VERSION 5.8 ;
BUSBITCHARS "[]" ;
DIVIDERCHAR "/" ;

UNITS
  DATABASE MICRONS 1000 ;
END UNITS

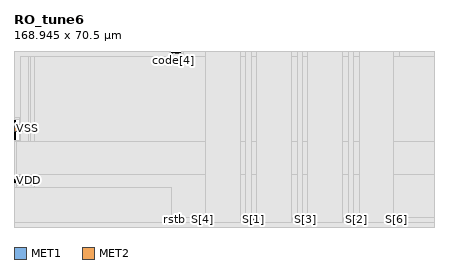
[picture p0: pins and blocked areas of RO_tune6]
MACRO RO_tune6
  CLASS BLOCK ;
  ORIGIN 68.7 88.515 ;
  FOREIGN RO_tune6 -68.7 -88.515 ;
  SIZE 168.945 BY 70.5 ;
  SYMMETRY X Y R90 ;
  PIN code[0]
    DIRECTION INPUT ;
    USE SIGNAL ;
    PORT
      LAYER MET1 ;
        RECT -2.775 -18.885 -2.545 -18.655 ;
    END
  END code[0]
  PIN code[7]
    DIRECTION INPUT ;
    USE SIGNAL ;
    PORT
      LAYER MET1 ;
        RECT -1.805 -18.885 -1.575 -18.655 ;
    END
  END code[7]
  PIN S[0]
    DIRECTION OUTPUT ;
    USE SIGNAL ;
    PORT
      LAYER MET2 ;
        RECT 23.305 -85.825 23.585 -85.545 ;
    END
  END S[0]
  PIN S[7]
    DIRECTION OUTPUT ;
    USE SIGNAL ;
    PORT
      LAYER MET2 ;
        RECT 64.455 -85.825 64.735 -85.545 ;
    END
  END S[7]
  PIN rstb
    DIRECTION INPUT ;
    USE SIGNAL ;
    PORT
      LAYER MET2 ;
        RECT -4.295 -85.825 -4.015 -85.545 ;
    END
  END rstb
  PIN code[1]
    DIRECTION INPUT ;
    USE SIGNAL ;
    PORT
      LAYER MET1 ;
        RECT -3.26 -18.885 -3.03 -18.655 ;
    END
  END code[1]
  PIN code[2]
    DIRECTION INPUT ;
    USE SIGNAL ;
    PORT
      LAYER MET1 ;
        RECT -3.745 -18.885 -3.515 -18.655 ;
    END
  END code[2]
  PIN code[3]
    DIRECTION INPUT ;
    USE SIGNAL ;
    PORT
      LAYER MET1 ;
        RECT -4.23 -18.885 -4 -18.655 ;
    END
  END code[3]
  PIN code[4]
    DIRECTION INPUT ;
    USE SIGNAL ;
    PORT
      LAYER MET1 ;
        RECT -4.715 -18.885 -4.485 -18.655 ;
    END
  END code[4]
  PIN code[5]
    DIRECTION INPUT ;
    USE SIGNAL ;
    PORT
      LAYER MET1 ;
        RECT -5.2 -18.885 -4.97 -18.655 ;
    END
  END code[5]
  PIN code[6]
    DIRECTION INPUT ;
    USE SIGNAL ;
    PORT
      LAYER MET1 ;
        RECT -2.29 -18.885 -2.06 -18.655 ;
    END
  END code[6]
  PIN VDD
    DIRECTION INOUT ;
    USE POWER ;
    PORT
      LAYER MET1 ;
        RECT -66.67 -71.56 -61.525 -68.325 ;
    END
  END VDD
  PIN VSS
    DIRECTION INOUT ;
    USE GROUND ;
    PORT
      LAYER MET2 ;
        RECT -68.64 -50.215 -63.035 -47.215 ;
    END
  END VSS
  PIN S[2]
    DIRECTION OUTPUT ;
    USE SIGNAL ;
    PORT
      LAYER MET2 ;
        RECT 68.805 -85.825 69.085 -85.545 ;
    END
  END S[2]
  PIN S[6]
    DIRECTION OUTPUT ;
    USE SIGNAL ;
    PORT
      LAYER MET2 ;
        RECT 85.03 -85.825 85.31 -85.545 ;
    END
  END S[6]
  PIN S[3]
    DIRECTION OUTPUT ;
    USE SIGNAL ;
    PORT
      LAYER MET2 ;
        RECT 48.23 -85.825 48.51 -85.545 ;
    END
  END S[3]
  PIN S[1]
    DIRECTION OUTPUT ;
    USE SIGNAL ;
    PORT
      LAYER MET2 ;
        RECT 27.655 -85.825 27.935 -85.545 ;
    END
  END S[1]
  PIN S[5]
    DIRECTION OUTPUT ;
    USE SIGNAL ;
    PORT
      LAYER MET2 ;
        RECT 43.91 -85.825 44.19 -85.545 ;
    END
  END S[5]
  PIN S[4]
    DIRECTION OUTPUT ;
    USE SIGNAL ;
    PORT
      LAYER MET2 ;
        RECT 7.08 -85.825 7.36 -85.545 ;
    END
  END S[4]
  OBS
    # MPTDC_OPTION_B2_PG_ACCESS_CUT
    LAYER MET1 ;
      RECT 99.25 -67.175 99.55 -57.125 ;
      RECT 98.13 -67.175 98.43 -57.125 ;
      RECT 97.01 -67.175 97.31 -57.125 ;
      RECT 95.89 -67.175 96.19 -57.125 ;
      RECT 95.76 -67.175 100.24 -66.755 ;
      RECT 99.81 -66.425 100.11 -46.325 ;
      RECT 98.69 -66.425 98.99 -46.325 ;
      RECT 97.57 -66.425 97.87 -46.325 ;
      RECT 96.45 -66.425 96.75 -46.325 ;
      RECT 95.76 -56.795 100.24 -55.955 ;
      RECT 99.25 -55.625 99.55 -35.525 ;
      RECT 98.13 -55.625 98.43 -35.525 ;
      RECT 97.01 -55.625 97.31 -35.525 ;
      RECT 95.89 -55.625 96.19 -35.525 ;
      RECT 95.76 -45.995 100.24 -45.155 ;
      RECT 99.81 -44.825 100.11 -24.725 ;
      RECT 98.69 -44.825 98.99 -24.725 ;
      RECT 97.57 -44.825 97.87 -24.725 ;
      RECT 96.45 -44.825 96.75 -24.725 ;
      RECT 95.76 -35.195 100.24 -34.355 ;
      RECT 95.76 -24.395 100.24 -23.975 ;
      RECT 99.25 -34.025 99.55 -23.975 ;
      RECT 98.13 -34.025 98.43 -23.975 ;
      RECT 97.01 -34.025 97.31 -23.975 ;
      RECT 95.89 -34.025 96.19 -23.975 ;
      RECT -1.805 -23.44 -1.575 -19.485 ;
      RECT -24.275 -23.465 -23.895 -23.185 ;
      RECT -24.275 -23.44 -1.575 -23.21 ;
      RECT -2.29 -22.955 -2.06 -19.485 ;
      RECT -29.065 -22.98 -28.685 -22.7 ;
      RECT -29.065 -22.955 -2.06 -22.725 ;
      RECT -2.775 -22.47 -2.545 -19.485 ;
      RECT -33.855 -22.495 -33.475 -22.215 ;
      RECT -33.855 -22.47 -2.545 -22.24 ;
      RECT -3.26 -21.985 -3.03 -19.485 ;
      RECT -38.645 -22.01 -38.265 -21.73 ;
      RECT -38.645 -21.985 -3.03 -21.755 ;
      RECT -3.745 -21.5 -3.515 -19.485 ;
      RECT -43.435 -21.525 -43.055 -21.245 ;
      RECT -43.435 -21.5 -3.515 -21.27 ;
      RECT -4.23 -21.015 -4 -19.485 ;
      RECT -48.285 -21.04 -47.905 -20.76 ;
      RECT -48.285 -21.015 -4 -20.785 ;
      RECT -4.715 -20.53 -4.485 -19.485 ;
      RECT -53.1 -20.555 -52.72 -20.275 ;
      RECT -53.1 -20.53 -4.485 -20.3 ;
      RECT -5.2 -20.045 -4.97 -19.485 ;
      RECT -57.805 -20.07 -57.425 -19.79 ;
      RECT -57.805 -20.045 -4.97 -19.815 ;
      RECT -68.695 -83.02 -67.015 -70.943 ;
      RECT -68.695 -68.942 -67.015 -53.915 ;
      RECT -68.695 -83.02 -8.41 -78.02 ;
      RECT -66.67 -67.725 -64.99 -36.465 ;
      RECT -68.695 -45.05 -67.015 -36.465 ;
      RECT -1.155 -88.515 100.245 -18.015 ;
      RECT -68.7 -45.23 -5.62 -18.015 ;
      RECT -60.525 -88.515 100.245 -19.305 ;
      RECT -61.105 -88.515 -60.525 -70.943 ;
      RECT -61.105 -68.942 -60.525 -19.305 ;
      RECT -66.67 -67.905 100.245 -19.305 ;
      RECT -68.7 -67.905 100.245 -53.735 ;
      RECT -68.7 -88.515 -67.015 -70.943 ;
      RECT -68.7 -68.942 -67.015 -53.735 ;
      RECT -68.7 -88.515 100.245 -71.98 ;
    LAYER MET2 ;
      RECT 99.26 -67.175 99.54 -57.125 ;
      RECT 98.14 -67.175 98.42 -57.125 ;
      RECT 97.02 -67.175 97.3 -57.125 ;
      RECT 95.9 -67.175 96.18 -57.125 ;
      RECT 95.76 -67.175 100.24 -66.775 ;
      RECT 99.82 -66.425 100.1 -46.325 ;
      RECT 98.7 -66.425 98.98 -46.325 ;
      RECT 97.58 -66.425 97.86 -46.325 ;
      RECT 96.46 -66.425 96.74 -46.325 ;
      RECT 95.76 -56.775 100.24 -55.975 ;
      RECT 99.26 -55.625 99.54 -35.525 ;
      RECT 98.14 -55.625 98.42 -35.525 ;
      RECT 97.02 -55.625 97.3 -35.525 ;
      RECT 95.9 -55.625 96.18 -35.525 ;
      RECT 95.76 -45.975 100.24 -45.175 ;
      RECT 99.82 -44.825 100.1 -24.725 ;
      RECT 98.7 -44.825 98.98 -24.725 ;
      RECT 97.58 -44.825 97.86 -24.725 ;
      RECT 96.46 -44.825 96.74 -24.725 ;
      RECT 95.76 -35.175 100.24 -34.375 ;
      RECT 95.76 -24.375 100.24 -23.975 ;
      RECT 99.26 -34.025 99.54 -23.975 ;
      RECT 98.14 -34.025 98.42 -23.975 ;
      RECT 97.02 -34.025 97.3 -23.975 ;
      RECT 95.9 -34.025 96.18 -23.975 ;
      RECT -11.66 -22.655 34.925 -18.655 ;
      RECT -68.64 -58.215 -63.415 -55.215 ;
      RECT -68.64 -66.215 -63.575 -63.215 ;
      RECT -0.575 -85.125 100.245 -18.015 ;
      RECT 85.73 -88.515 100.245 -18.015 ;
      RECT -68.7 -44.65 -6.2 -18.015 ;
      RECT -3.595 -88.515 6.66 -18.655 ;
      RECT -62.035 -67.325 100.245 -18.655 ;
      RECT -62.985 -67.325 -62.035 -49.715 ;
      RECT -62.985 -47.715 -62.035 -18.655 ;
      RECT -66.015 -67.325 -62.985 -50.265 ;
      RECT -66.015 -47.165 -62.985 -18.655 ;
      RECT -60.525 -85.125 100.245 -18.655 ;
      RECT -62.035 -50.215 100.245 -47.215 ;
      RECT -62.985 -50.215 -62.035 -49.715 ;
      RECT -62.985 -47.715 -62.035 -47.215 ;
      RECT -68.7 -67.325 100.245 -54.315 ;
      RECT -68.7 -88.515 -67.67 -70.943 ;
      RECT -68.7 -68.942 -67.67 -54.315 ;
      RECT -68.7 -88.515 -4.715 -72.56 ;
      RECT 69.505 -88.515 84.61 -18.015 ;
      RECT 65.155 -88.515 68.385 -18.015 ;
      RECT 48.93 -88.515 64.035 -18.015 ;
      RECT 44.61 -88.515 47.81 -18.015 ;
      RECT 28.355 -88.515 43.49 -18.015 ;
      RECT 24.005 -88.515 27.235 -18.015 ;
      RECT 7.78 -88.515 22.885 -18.015 ;
      RECT -68.7 -88.515 100.245 -86.245 ;
    LAYER MET3 ;
      RECT 99.26 -67.175 99.54 -57.325 ;
      RECT 98.14 -67.175 98.42 -57.325 ;
      RECT 97.02 -67.175 97.3 -57.325 ;
      RECT 95.9 -67.175 96.18 -57.325 ;
      RECT 95.76 -67.175 100.24 -66.575 ;
      RECT 99.82 -66.225 100.1 -46.525 ;
      RECT 98.7 -66.225 98.98 -46.525 ;
      RECT 97.58 -66.225 97.86 -46.525 ;
      RECT 96.46 -66.225 96.74 -46.525 ;
      RECT 95.76 -56.975 100.24 -55.775 ;
      RECT 99.26 -55.425 99.54 -35.725 ;
      RECT 98.14 -55.425 98.42 -35.725 ;
      RECT 97.02 -55.425 97.3 -35.725 ;
      RECT 95.9 -55.425 96.18 -35.725 ;
      RECT 95.76 -46.175 100.24 -44.975 ;
      RECT 99.82 -44.625 100.1 -24.925 ;
      RECT 98.7 -44.625 98.98 -24.925 ;
      RECT 97.58 -44.625 97.86 -24.925 ;
      RECT 96.46 -44.625 96.74 -24.925 ;
      RECT 95.76 -35.375 100.24 -34.175 ;
      RECT 95.76 -24.575 100.24 -23.975 ;
      RECT 99.26 -33.825 99.54 -23.975 ;
      RECT 98.14 -33.825 98.42 -23.975 ;
      RECT 97.02 -33.825 97.3 -23.975 ;
      RECT 95.9 -33.825 96.18 -23.975 ;
      RECT -0.575 -84.545 100.245 -18.015 ;
      RECT 86.31 -88.515 100.245 -18.015 ;
      RECT -68.7 -44.65 -6.2 -18.015 ;
      RECT -3.015 -88.515 6.08 -19.885 ;
      RECT -62.035 -67.325 100.245 -19.885 ;
      RECT -62.985 -67.325 -62.035 -49.715 ;
      RECT -62.985 -47.715 -62.035 -19.885 ;
      RECT -66.015 -67.325 -62.985 -50.265 ;
      RECT -66.015 -47.165 -62.985 -19.885 ;
      RECT -60.525 -84.545 100.245 -19.885 ;
      RECT -68.7 -67.325 100.245 -54.315 ;
      RECT -68.7 -88.515 -67.67 -70.943 ;
      RECT -68.7 -68.942 -67.67 -54.315 ;
      RECT -68.7 -88.515 -5.295 -72.56 ;
      RECT 70.085 -88.515 84.03 -18.015 ;
      RECT 65.735 -88.515 67.805 -18.015 ;
      RECT 49.51 -88.515 63.455 -18.015 ;
      RECT 45.19 -88.515 47.23 -18.015 ;
      RECT 28.935 -88.515 42.91 -18.015 ;
      RECT 24.585 -88.515 26.655 -18.015 ;
      RECT 8.36 -88.515 22.305 -18.015 ;
      RECT -68.7 -88.515 100.245 -86.825 ;
      RECT -0.575 -84.545 100.245 -18.015 ;
      RECT 86.31 -88.515 100.245 -18.015 ;
      RECT -68.7 -44.65 -6.2 -18.015 ;
      RECT -3.015 -88.515 6.08 -19.885 ;
      RECT -62.035 -67.325 100.245 -19.885 ;
      RECT -62.985 -67.325 -62.035 -49.715 ;
      RECT -62.985 -47.715 -62.035 -19.885 ;
      RECT -66.015 -67.325 -62.985 -50.265 ;
      RECT -66.015 -47.165 -62.985 -19.885 ;
      RECT -60.525 -84.545 100.245 -19.885 ;
      RECT -68.7 -67.325 100.245 -54.315 ;
      RECT -68.7 -88.515 -67.67 -70.943 ;
      RECT -68.7 -68.942 -67.67 -54.315 ;
      RECT -68.7 -88.515 -5.295 -72.56 ;
      RECT 70.085 -88.515 84.03 -18.015 ;
      RECT 65.735 -88.515 67.805 -18.015 ;
      RECT 49.51 -88.515 63.455 -18.015 ;
      RECT 45.19 -88.515 47.23 -18.015 ;
      RECT 28.935 -88.515 42.91 -18.015 ;
      RECT 24.585 -88.515 26.655 -18.015 ;
      RECT 8.36 -88.515 22.305 -18.015 ;
      RECT -68.7 -88.515 100.245 -86.825 ;
  END
  PROPERTY CatenaDesignType "mixed" ;
END RO_tune6
END LIBRARY
